VERSION 5.7 ;
  NOWIREEXTENSIONATPIN ON ;
  DIVIDERCHAR "/" ;
  BUSBITCHARS "[]" ;
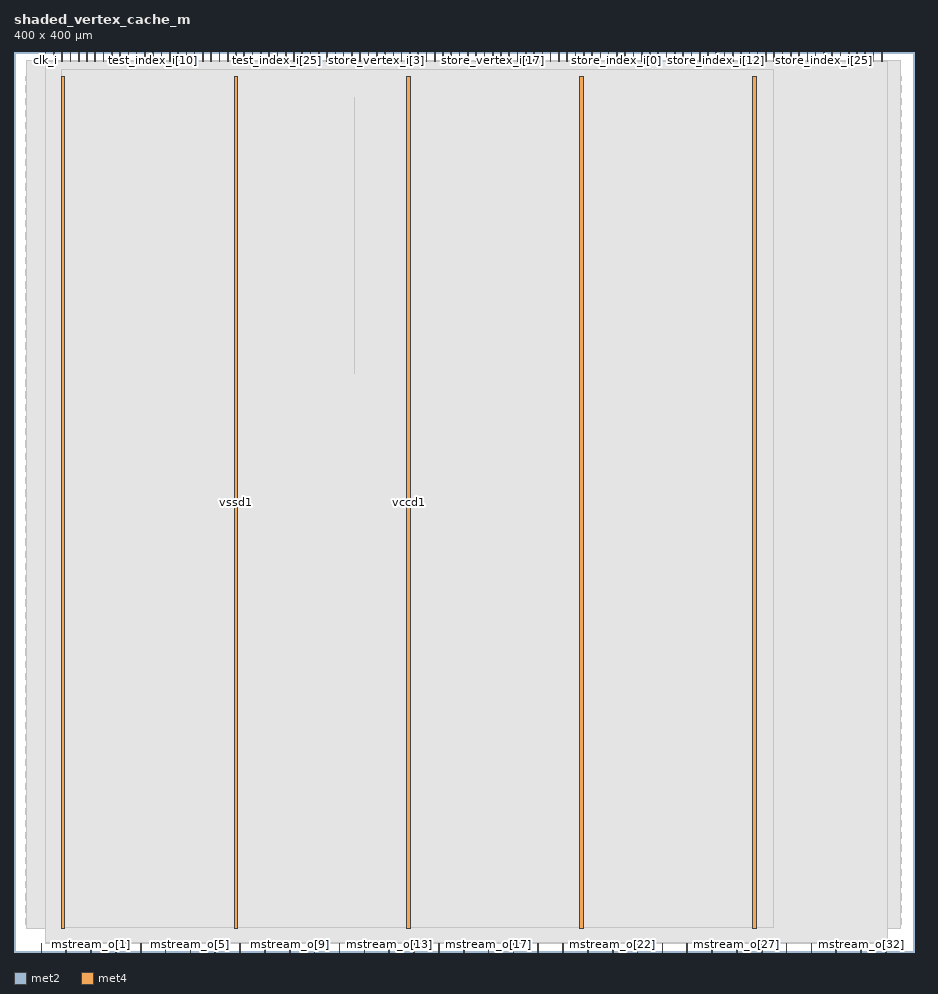
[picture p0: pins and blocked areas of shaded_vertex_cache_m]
MACRO shaded_vertex_cache_m
  CLASS BLOCK ;
  FOREIGN shaded_vertex_cache_m ;
  ORIGIN 0.000 0.000 ;
  SIZE 400.000 BY 400.000 ;
  PIN clear_i
    DIRECTION INPUT ;
    USE SIGNAL ;
    ANTENNAGATEAREA 0.196500 ;
    PORT
      LAYER met2 ;
        RECT 21.250 396.000 21.530 400.000 ;
    END
  END clear_i
  PIN clk_i
    DIRECTION INPUT ;
    USE SIGNAL ;
    ANTENNAGATEAREA 0.852000 ;
    PORT
      LAYER met2 ;
        RECT 13.890 396.000 14.170 400.000 ;
    END
  END clk_i
  PIN mstream_i
    DIRECTION INPUT ;
    USE SIGNAL ;
    PORT
      LAYER met2 ;
        RECT 12.050 0.000 12.330 4.000 ;
    END
  END mstream_i
  PIN mstream_o[0]
    DIRECTION OUTPUT TRISTATE ;
    USE SIGNAL ;
    ANTENNADIFFAREA 2.673000 ;
    PORT
      LAYER met2 ;
        RECT 23.090 0.000 23.370 4.000 ;
    END
  END mstream_o[0]
  PIN mstream_o[10]
    DIRECTION OUTPUT TRISTATE ;
    USE SIGNAL ;
    ANTENNADIFFAREA 2.673000 ;
    PORT
      LAYER met2 ;
        RECT 133.490 0.000 133.770 4.000 ;
    END
  END mstream_o[10]
  PIN mstream_o[11]
    DIRECTION OUTPUT TRISTATE ;
    USE SIGNAL ;
    ANTENNADIFFAREA 2.673000 ;
    PORT
      LAYER met2 ;
        RECT 144.530 0.000 144.810 4.000 ;
    END
  END mstream_o[11]
  PIN mstream_o[12]
    DIRECTION OUTPUT TRISTATE ;
    USE SIGNAL ;
    ANTENNADIFFAREA 2.673000 ;
    PORT
      LAYER met2 ;
        RECT 155.570 0.000 155.850 4.000 ;
    END
  END mstream_o[12]
  PIN mstream_o[13]
    DIRECTION OUTPUT TRISTATE ;
    USE SIGNAL ;
    ANTENNADIFFAREA 2.673000 ;
    PORT
      LAYER met2 ;
        RECT 166.610 0.000 166.890 4.000 ;
    END
  END mstream_o[13]
  PIN mstream_o[14]
    DIRECTION OUTPUT TRISTATE ;
    USE SIGNAL ;
    ANTENNADIFFAREA 2.673000 ;
    PORT
      LAYER met2 ;
        RECT 177.650 0.000 177.930 4.000 ;
    END
  END mstream_o[14]
  PIN mstream_o[15]
    DIRECTION OUTPUT TRISTATE ;
    USE SIGNAL ;
    ANTENNADIFFAREA 2.673000 ;
    PORT
      LAYER met2 ;
        RECT 188.690 0.000 188.970 4.000 ;
    END
  END mstream_o[15]
  PIN mstream_o[16]
    DIRECTION OUTPUT TRISTATE ;
    USE SIGNAL ;
    ANTENNADIFFAREA 2.673000 ;
    PORT
      LAYER met2 ;
        RECT 199.730 0.000 200.010 4.000 ;
    END
  END mstream_o[16]
  PIN mstream_o[17]
    DIRECTION OUTPUT TRISTATE ;
    USE SIGNAL ;
    ANTENNADIFFAREA 2.673000 ;
    PORT
      LAYER met2 ;
        RECT 210.770 0.000 211.050 4.000 ;
    END
  END mstream_o[17]
  PIN mstream_o[18]
    DIRECTION OUTPUT TRISTATE ;
    USE SIGNAL ;
    ANTENNADIFFAREA 2.673000 ;
    PORT
      LAYER met2 ;
        RECT 221.810 0.000 222.090 4.000 ;
    END
  END mstream_o[18]
  PIN mstream_o[19]
    DIRECTION OUTPUT TRISTATE ;
    USE SIGNAL ;
    ANTENNADIFFAREA 2.673000 ;
    PORT
      LAYER met2 ;
        RECT 232.850 0.000 233.130 4.000 ;
    END
  END mstream_o[19]
  PIN mstream_o[1]
    DIRECTION OUTPUT TRISTATE ;
    USE SIGNAL ;
    ANTENNADIFFAREA 2.673000 ;
    PORT
      LAYER met2 ;
        RECT 34.130 0.000 34.410 4.000 ;
    END
  END mstream_o[1]
  PIN mstream_o[20]
    DIRECTION OUTPUT TRISTATE ;
    USE SIGNAL ;
    ANTENNADIFFAREA 2.673000 ;
    PORT
      LAYER met2 ;
        RECT 243.890 0.000 244.170 4.000 ;
    END
  END mstream_o[20]
  PIN mstream_o[21]
    DIRECTION OUTPUT TRISTATE ;
    USE SIGNAL ;
    ANTENNADIFFAREA 2.673000 ;
    PORT
      LAYER met2 ;
        RECT 254.930 0.000 255.210 4.000 ;
    END
  END mstream_o[21]
  PIN mstream_o[22]
    DIRECTION OUTPUT TRISTATE ;
    USE SIGNAL ;
    ANTENNADIFFAREA 2.673000 ;
    PORT
      LAYER met2 ;
        RECT 265.970 0.000 266.250 4.000 ;
    END
  END mstream_o[22]
  PIN mstream_o[23]
    DIRECTION OUTPUT TRISTATE ;
    USE SIGNAL ;
    ANTENNADIFFAREA 2.673000 ;
    PORT
      LAYER met2 ;
        RECT 277.010 0.000 277.290 4.000 ;
    END
  END mstream_o[23]
  PIN mstream_o[24]
    DIRECTION OUTPUT TRISTATE ;
    USE SIGNAL ;
    ANTENNADIFFAREA 2.673000 ;
    PORT
      LAYER met2 ;
        RECT 288.050 0.000 288.330 4.000 ;
    END
  END mstream_o[24]
  PIN mstream_o[25]
    DIRECTION OUTPUT TRISTATE ;
    USE SIGNAL ;
    ANTENNADIFFAREA 2.673000 ;
    PORT
      LAYER met2 ;
        RECT 299.090 0.000 299.370 4.000 ;
    END
  END mstream_o[25]
  PIN mstream_o[26]
    DIRECTION OUTPUT TRISTATE ;
    USE SIGNAL ;
    ANTENNADIFFAREA 2.673000 ;
    PORT
      LAYER met2 ;
        RECT 310.130 0.000 310.410 4.000 ;
    END
  END mstream_o[26]
  PIN mstream_o[27]
    DIRECTION OUTPUT TRISTATE ;
    USE SIGNAL ;
    ANTENNADIFFAREA 2.673000 ;
    PORT
      LAYER met2 ;
        RECT 321.170 0.000 321.450 4.000 ;
    END
  END mstream_o[27]
  PIN mstream_o[28]
    DIRECTION OUTPUT TRISTATE ;
    USE SIGNAL ;
    ANTENNADIFFAREA 2.673000 ;
    PORT
      LAYER met2 ;
        RECT 332.210 0.000 332.490 4.000 ;
    END
  END mstream_o[28]
  PIN mstream_o[29]
    DIRECTION OUTPUT TRISTATE ;
    USE SIGNAL ;
    ANTENNADIFFAREA 2.673000 ;
    PORT
      LAYER met2 ;
        RECT 343.250 0.000 343.530 4.000 ;
    END
  END mstream_o[29]
  PIN mstream_o[2]
    DIRECTION OUTPUT TRISTATE ;
    USE SIGNAL ;
    ANTENNADIFFAREA 2.673000 ;
    PORT
      LAYER met2 ;
        RECT 45.170 0.000 45.450 4.000 ;
    END
  END mstream_o[2]
  PIN mstream_o[30]
    DIRECTION OUTPUT TRISTATE ;
    USE SIGNAL ;
    ANTENNADIFFAREA 2.673000 ;
    PORT
      LAYER met2 ;
        RECT 354.290 0.000 354.570 4.000 ;
    END
  END mstream_o[30]
  PIN mstream_o[31]
    DIRECTION OUTPUT TRISTATE ;
    USE SIGNAL ;
    ANTENNADIFFAREA 2.673000 ;
    PORT
      LAYER met2 ;
        RECT 365.330 0.000 365.610 4.000 ;
    END
  END mstream_o[31]
  PIN mstream_o[32]
    DIRECTION OUTPUT TRISTATE ;
    USE SIGNAL ;
    ANTENNADIFFAREA 2.673000 ;
    PORT
      LAYER met2 ;
        RECT 376.370 0.000 376.650 4.000 ;
    END
  END mstream_o[32]
  PIN mstream_o[33]
    DIRECTION OUTPUT TRISTATE ;
    USE SIGNAL ;
    PORT
      LAYER met2 ;
        RECT 387.410 0.000 387.690 4.000 ;
    END
  END mstream_o[33]
  PIN mstream_o[3]
    DIRECTION OUTPUT TRISTATE ;
    USE SIGNAL ;
    ANTENNADIFFAREA 2.673000 ;
    PORT
      LAYER met2 ;
        RECT 56.210 0.000 56.490 4.000 ;
    END
  END mstream_o[3]
  PIN mstream_o[4]
    DIRECTION OUTPUT TRISTATE ;
    USE SIGNAL ;
    ANTENNADIFFAREA 2.673000 ;
    PORT
      LAYER met2 ;
        RECT 67.250 0.000 67.530 4.000 ;
    END
  END mstream_o[4]
  PIN mstream_o[5]
    DIRECTION OUTPUT TRISTATE ;
    USE SIGNAL ;
    ANTENNADIFFAREA 2.673000 ;
    PORT
      LAYER met2 ;
        RECT 78.290 0.000 78.570 4.000 ;
    END
  END mstream_o[5]
  PIN mstream_o[6]
    DIRECTION OUTPUT TRISTATE ;
    USE SIGNAL ;
    ANTENNADIFFAREA 2.673000 ;
    PORT
      LAYER met2 ;
        RECT 89.330 0.000 89.610 4.000 ;
    END
  END mstream_o[6]
  PIN mstream_o[7]
    DIRECTION OUTPUT TRISTATE ;
    USE SIGNAL ;
    ANTENNADIFFAREA 2.673000 ;
    PORT
      LAYER met2 ;
        RECT 100.370 0.000 100.650 4.000 ;
    END
  END mstream_o[7]
  PIN mstream_o[8]
    DIRECTION OUTPUT TRISTATE ;
    USE SIGNAL ;
    ANTENNADIFFAREA 2.673000 ;
    PORT
      LAYER met2 ;
        RECT 111.410 0.000 111.690 4.000 ;
    END
  END mstream_o[8]
  PIN mstream_o[9]
    DIRECTION OUTPUT TRISTATE ;
    USE SIGNAL ;
    ANTENNADIFFAREA 2.673000 ;
    PORT
      LAYER met2 ;
        RECT 122.450 0.000 122.730 4.000 ;
    END
  END mstream_o[9]
  PIN nrst_i
    DIRECTION INPUT ;
    USE SIGNAL ;
    ANTENNAGATEAREA 0.213000 ;
    PORT
      LAYER met2 ;
        RECT 17.570 396.000 17.850 400.000 ;
    END
  END nrst_i
  PIN store_index_i[0]
    DIRECTION INPUT ;
    USE SIGNAL ;
    ANTENNAGATEAREA 0.196500 ;
    PORT
      LAYER met2 ;
        RECT 267.810 396.000 268.090 400.000 ;
    END
  END store_index_i[0]
  PIN store_index_i[10]
    DIRECTION INPUT ;
    USE SIGNAL ;
    ANTENNAGATEAREA 0.196500 ;
    PORT
      LAYER met2 ;
        RECT 304.610 396.000 304.890 400.000 ;
    END
  END store_index_i[10]
  PIN store_index_i[11]
    DIRECTION INPUT ;
    USE SIGNAL ;
    ANTENNAGATEAREA 0.196500 ;
    PORT
      LAYER met2 ;
        RECT 308.290 396.000 308.570 400.000 ;
    END
  END store_index_i[11]
  PIN store_index_i[12]
    DIRECTION INPUT ;
    USE SIGNAL ;
    ANTENNAGATEAREA 0.196500 ;
    PORT
      LAYER met2 ;
        RECT 311.970 396.000 312.250 400.000 ;
    END
  END store_index_i[12]
  PIN store_index_i[13]
    DIRECTION INPUT ;
    USE SIGNAL ;
    ANTENNAGATEAREA 0.196500 ;
    PORT
      LAYER met2 ;
        RECT 315.650 396.000 315.930 400.000 ;
    END
  END store_index_i[13]
  PIN store_index_i[14]
    DIRECTION INPUT ;
    USE SIGNAL ;
    ANTENNAGATEAREA 0.196500 ;
    PORT
      LAYER met2 ;
        RECT 319.330 396.000 319.610 400.000 ;
    END
  END store_index_i[14]
  PIN store_index_i[15]
    DIRECTION INPUT ;
    USE SIGNAL ;
    ANTENNAGATEAREA 0.196500 ;
    PORT
      LAYER met2 ;
        RECT 323.010 396.000 323.290 400.000 ;
    END
  END store_index_i[15]
  PIN store_index_i[16]
    DIRECTION INPUT ;
    USE SIGNAL ;
    ANTENNAGATEAREA 0.196500 ;
    PORT
      LAYER met2 ;
        RECT 326.690 396.000 326.970 400.000 ;
    END
  END store_index_i[16]
  PIN store_index_i[17]
    DIRECTION INPUT ;
    USE SIGNAL ;
    ANTENNAGATEAREA 0.126000 ;
    PORT
      LAYER met2 ;
        RECT 330.370 396.000 330.650 400.000 ;
    END
  END store_index_i[17]
  PIN store_index_i[18]
    DIRECTION INPUT ;
    USE SIGNAL ;
    ANTENNAGATEAREA 0.196500 ;
    PORT
      LAYER met2 ;
        RECT 334.050 396.000 334.330 400.000 ;
    END
  END store_index_i[18]
  PIN store_index_i[19]
    DIRECTION INPUT ;
    USE SIGNAL ;
    ANTENNAGATEAREA 0.196500 ;
    PORT
      LAYER met2 ;
        RECT 337.730 396.000 338.010 400.000 ;
    END
  END store_index_i[19]
  PIN store_index_i[1]
    DIRECTION INPUT ;
    USE SIGNAL ;
    ANTENNAGATEAREA 0.196500 ;
    PORT
      LAYER met2 ;
        RECT 271.490 396.000 271.770 400.000 ;
    END
  END store_index_i[1]
  PIN store_index_i[20]
    DIRECTION INPUT ;
    USE SIGNAL ;
    ANTENNAGATEAREA 0.196500 ;
    PORT
      LAYER met2 ;
        RECT 341.410 396.000 341.690 400.000 ;
    END
  END store_index_i[20]
  PIN store_index_i[21]
    DIRECTION INPUT ;
    USE SIGNAL ;
    ANTENNAGATEAREA 0.213000 ;
    PORT
      LAYER met2 ;
        RECT 345.090 396.000 345.370 400.000 ;
    END
  END store_index_i[21]
  PIN store_index_i[22]
    DIRECTION INPUT ;
    USE SIGNAL ;
    ANTENNAGATEAREA 0.213000 ;
    PORT
      LAYER met2 ;
        RECT 348.770 396.000 349.050 400.000 ;
    END
  END store_index_i[22]
  PIN store_index_i[23]
    DIRECTION INPUT ;
    USE SIGNAL ;
    ANTENNAGATEAREA 0.213000 ;
    PORT
      LAYER met2 ;
        RECT 352.450 396.000 352.730 400.000 ;
    END
  END store_index_i[23]
  PIN store_index_i[24]
    DIRECTION INPUT ;
    USE SIGNAL ;
    ANTENNAGATEAREA 0.213000 ;
    PORT
      LAYER met2 ;
        RECT 356.130 396.000 356.410 400.000 ;
    END
  END store_index_i[24]
  PIN store_index_i[25]
    DIRECTION INPUT ;
    USE SIGNAL ;
    ANTENNAGATEAREA 0.213000 ;
    PORT
      LAYER met2 ;
        RECT 359.810 396.000 360.090 400.000 ;
    END
  END store_index_i[25]
  PIN store_index_i[26]
    DIRECTION INPUT ;
    USE SIGNAL ;
    ANTENNAGATEAREA 0.213000 ;
    PORT
      LAYER met2 ;
        RECT 363.490 396.000 363.770 400.000 ;
    END
  END store_index_i[26]
  PIN store_index_i[27]
    DIRECTION INPUT ;
    USE SIGNAL ;
    ANTENNAGATEAREA 0.213000 ;
    PORT
      LAYER met2 ;
        RECT 367.170 396.000 367.450 400.000 ;
    END
  END store_index_i[27]
  PIN store_index_i[28]
    DIRECTION INPUT ;
    USE SIGNAL ;
    ANTENNAGATEAREA 0.213000 ;
    PORT
      LAYER met2 ;
        RECT 370.850 396.000 371.130 400.000 ;
    END
  END store_index_i[28]
  PIN store_index_i[29]
    DIRECTION INPUT ;
    USE SIGNAL ;
    ANTENNAGATEAREA 0.213000 ;
    PORT
      LAYER met2 ;
        RECT 374.530 396.000 374.810 400.000 ;
    END
  END store_index_i[29]
  PIN store_index_i[2]
    DIRECTION INPUT ;
    USE SIGNAL ;
    ANTENNAGATEAREA 0.196500 ;
    PORT
      LAYER met2 ;
        RECT 275.170 396.000 275.450 400.000 ;
    END
  END store_index_i[2]
  PIN store_index_i[30]
    DIRECTION INPUT ;
    USE SIGNAL ;
    ANTENNAGATEAREA 0.213000 ;
    PORT
      LAYER met2 ;
        RECT 378.210 396.000 378.490 400.000 ;
    END
  END store_index_i[30]
  PIN store_index_i[31]
    DIRECTION INPUT ;
    USE SIGNAL ;
    ANTENNAGATEAREA 0.196500 ;
    PORT
      LAYER met2 ;
        RECT 381.890 396.000 382.170 400.000 ;
    END
  END store_index_i[31]
  PIN store_index_i[3]
    DIRECTION INPUT ;
    USE SIGNAL ;
    ANTENNAGATEAREA 0.196500 ;
    PORT
      LAYER met2 ;
        RECT 278.850 396.000 279.130 400.000 ;
    END
  END store_index_i[3]
  PIN store_index_i[4]
    DIRECTION INPUT ;
    USE SIGNAL ;
    ANTENNAGATEAREA 0.196500 ;
    PORT
      LAYER met2 ;
        RECT 282.530 396.000 282.810 400.000 ;
    END
  END store_index_i[4]
  PIN store_index_i[5]
    DIRECTION INPUT ;
    USE SIGNAL ;
    ANTENNAGATEAREA 0.196500 ;
    PORT
      LAYER met2 ;
        RECT 286.210 396.000 286.490 400.000 ;
    END
  END store_index_i[5]
  PIN store_index_i[6]
    DIRECTION INPUT ;
    USE SIGNAL ;
    ANTENNAGATEAREA 0.196500 ;
    PORT
      LAYER met2 ;
        RECT 289.890 396.000 290.170 400.000 ;
    END
  END store_index_i[6]
  PIN store_index_i[7]
    DIRECTION INPUT ;
    USE SIGNAL ;
    ANTENNAGATEAREA 0.196500 ;
    PORT
      LAYER met2 ;
        RECT 293.570 396.000 293.850 400.000 ;
    END
  END store_index_i[7]
  PIN store_index_i[8]
    DIRECTION INPUT ;
    USE SIGNAL ;
    ANTENNAGATEAREA 0.196500 ;
    PORT
      LAYER met2 ;
        RECT 297.250 396.000 297.530 400.000 ;
    END
  END store_index_i[8]
  PIN store_index_i[9]
    DIRECTION INPUT ;
    USE SIGNAL ;
    ANTENNAGATEAREA 0.196500 ;
    PORT
      LAYER met2 ;
        RECT 300.930 396.000 301.210 400.000 ;
    END
  END store_index_i[9]
  PIN store_valid_i
    DIRECTION INPUT ;
    USE SIGNAL ;
    ANTENNAGATEAREA 0.213000 ;
    PORT
      LAYER met2 ;
        RECT 385.570 396.000 385.850 400.000 ;
    END
  END store_valid_i
  PIN store_vertex_i[0]
    DIRECTION INPUT ;
    USE SIGNAL ;
    ANTENNAGATEAREA 0.126000 ;
    PORT
      LAYER met2 ;
        RECT 150.050 396.000 150.330 400.000 ;
    END
  END store_vertex_i[0]
  PIN store_vertex_i[10]
    DIRECTION INPUT ;
    USE SIGNAL ;
    ANTENNAGATEAREA 0.196500 ;
    PORT
      LAYER met2 ;
        RECT 186.850 396.000 187.130 400.000 ;
    END
  END store_vertex_i[10]
  PIN store_vertex_i[11]
    DIRECTION INPUT ;
    USE SIGNAL ;
    ANTENNAGATEAREA 0.196500 ;
    PORT
      LAYER met2 ;
        RECT 190.530 396.000 190.810 400.000 ;
    END
  END store_vertex_i[11]
  PIN store_vertex_i[12]
    DIRECTION INPUT ;
    USE SIGNAL ;
    ANTENNAGATEAREA 0.196500 ;
    PORT
      LAYER met2 ;
        RECT 194.210 396.000 194.490 400.000 ;
    END
  END store_vertex_i[12]
  PIN store_vertex_i[13]
    DIRECTION INPUT ;
    USE SIGNAL ;
    ANTENNAGATEAREA 0.196500 ;
    PORT
      LAYER met2 ;
        RECT 197.890 396.000 198.170 400.000 ;
    END
  END store_vertex_i[13]
  PIN store_vertex_i[14]
    DIRECTION INPUT ;
    USE SIGNAL ;
    ANTENNAGATEAREA 0.196500 ;
    PORT
      LAYER met2 ;
        RECT 201.570 396.000 201.850 400.000 ;
    END
  END store_vertex_i[14]
  PIN store_vertex_i[15]
    DIRECTION INPUT ;
    USE SIGNAL ;
    ANTENNAGATEAREA 0.196500 ;
    PORT
      LAYER met2 ;
        RECT 205.250 396.000 205.530 400.000 ;
    END
  END store_vertex_i[15]
  PIN store_vertex_i[16]
    DIRECTION INPUT ;
    USE SIGNAL ;
    ANTENNAGATEAREA 0.196500 ;
    PORT
      LAYER met2 ;
        RECT 208.930 396.000 209.210 400.000 ;
    END
  END store_vertex_i[16]
  PIN store_vertex_i[17]
    DIRECTION INPUT ;
    USE SIGNAL ;
    ANTENNAGATEAREA 0.196500 ;
    PORT
      LAYER met2 ;
        RECT 212.610 396.000 212.890 400.000 ;
    END
  END store_vertex_i[17]
  PIN store_vertex_i[18]
    DIRECTION INPUT ;
    USE SIGNAL ;
    ANTENNAGATEAREA 0.196500 ;
    PORT
      LAYER met2 ;
        RECT 216.290 396.000 216.570 400.000 ;
    END
  END store_vertex_i[18]
  PIN store_vertex_i[19]
    DIRECTION INPUT ;
    USE SIGNAL ;
    ANTENNAGATEAREA 0.196500 ;
    PORT
      LAYER met2 ;
        RECT 219.970 396.000 220.250 400.000 ;
    END
  END store_vertex_i[19]
  PIN store_vertex_i[1]
    DIRECTION INPUT ;
    USE SIGNAL ;
    ANTENNAGATEAREA 0.196500 ;
    PORT
      LAYER met2 ;
        RECT 153.730 396.000 154.010 400.000 ;
    END
  END store_vertex_i[1]
  PIN store_vertex_i[20]
    DIRECTION INPUT ;
    USE SIGNAL ;
    ANTENNAGATEAREA 0.196500 ;
    PORT
      LAYER met2 ;
        RECT 223.650 396.000 223.930 400.000 ;
    END
  END store_vertex_i[20]
  PIN store_vertex_i[21]
    DIRECTION INPUT ;
    USE SIGNAL ;
    ANTENNAGATEAREA 0.196500 ;
    PORT
      LAYER met2 ;
        RECT 227.330 396.000 227.610 400.000 ;
    END
  END store_vertex_i[21]
  PIN store_vertex_i[22]
    DIRECTION INPUT ;
    USE SIGNAL ;
    ANTENNAGATEAREA 0.196500 ;
    PORT
      LAYER met2 ;
        RECT 231.010 396.000 231.290 400.000 ;
    END
  END store_vertex_i[22]
  PIN store_vertex_i[23]
    DIRECTION INPUT ;
    USE SIGNAL ;
    ANTENNAGATEAREA 0.196500 ;
    PORT
      LAYER met2 ;
        RECT 234.690 396.000 234.970 400.000 ;
    END
  END store_vertex_i[23]
  PIN store_vertex_i[24]
    DIRECTION INPUT ;
    USE SIGNAL ;
    ANTENNAGATEAREA 0.196500 ;
    PORT
      LAYER met2 ;
        RECT 238.370 396.000 238.650 400.000 ;
    END
  END store_vertex_i[24]
  PIN store_vertex_i[25]
    DIRECTION INPUT ;
    USE SIGNAL ;
    ANTENNAGATEAREA 0.196500 ;
    PORT
      LAYER met2 ;
        RECT 242.050 396.000 242.330 400.000 ;
    END
  END store_vertex_i[25]
  PIN store_vertex_i[26]
    DIRECTION INPUT ;
    USE SIGNAL ;
    ANTENNAGATEAREA 0.196500 ;
    PORT
      LAYER met2 ;
        RECT 245.730 396.000 246.010 400.000 ;
    END
  END store_vertex_i[26]
  PIN store_vertex_i[27]
    DIRECTION INPUT ;
    USE SIGNAL ;
    ANTENNAGATEAREA 0.196500 ;
    PORT
      LAYER met2 ;
        RECT 249.410 396.000 249.690 400.000 ;
    END
  END store_vertex_i[27]
  PIN store_vertex_i[28]
    DIRECTION INPUT ;
    USE SIGNAL ;
    ANTENNAGATEAREA 0.196500 ;
    PORT
      LAYER met2 ;
        RECT 253.090 396.000 253.370 400.000 ;
    END
  END store_vertex_i[28]
  PIN store_vertex_i[29]
    DIRECTION INPUT ;
    USE SIGNAL ;
    ANTENNAGATEAREA 0.196500 ;
    PORT
      LAYER met2 ;
        RECT 256.770 396.000 257.050 400.000 ;
    END
  END store_vertex_i[29]
  PIN store_vertex_i[2]
    DIRECTION INPUT ;
    USE SIGNAL ;
    ANTENNAGATEAREA 0.196500 ;
    PORT
      LAYER met2 ;
        RECT 157.410 396.000 157.690 400.000 ;
    END
  END store_vertex_i[2]
  PIN store_vertex_i[30]
    DIRECTION INPUT ;
    USE SIGNAL ;
    ANTENNAGATEAREA 0.196500 ;
    PORT
      LAYER met2 ;
        RECT 260.450 396.000 260.730 400.000 ;
    END
  END store_vertex_i[30]
  PIN store_vertex_i[31]
    DIRECTION INPUT ;
    USE SIGNAL ;
    ANTENNAGATEAREA 0.196500 ;
    PORT
      LAYER met2 ;
        RECT 264.130 396.000 264.410 400.000 ;
    END
  END store_vertex_i[31]
  PIN store_vertex_i[3]
    DIRECTION INPUT ;
    USE SIGNAL ;
    ANTENNAGATEAREA 0.196500 ;
    PORT
      LAYER met2 ;
        RECT 161.090 396.000 161.370 400.000 ;
    END
  END store_vertex_i[3]
  PIN store_vertex_i[4]
    DIRECTION INPUT ;
    USE SIGNAL ;
    ANTENNAGATEAREA 0.196500 ;
    PORT
      LAYER met2 ;
        RECT 164.770 396.000 165.050 400.000 ;
    END
  END store_vertex_i[4]
  PIN store_vertex_i[5]
    DIRECTION INPUT ;
    USE SIGNAL ;
    ANTENNAGATEAREA 0.196500 ;
    PORT
      LAYER met2 ;
        RECT 168.450 396.000 168.730 400.000 ;
    END
  END store_vertex_i[5]
  PIN store_vertex_i[6]
    DIRECTION INPUT ;
    USE SIGNAL ;
    ANTENNAGATEAREA 0.196500 ;
    PORT
      LAYER met2 ;
        RECT 172.130 396.000 172.410 400.000 ;
    END
  END store_vertex_i[6]
  PIN store_vertex_i[7]
    DIRECTION INPUT ;
    USE SIGNAL ;
    ANTENNAGATEAREA 0.196500 ;
    PORT
      LAYER met2 ;
        RECT 175.810 396.000 176.090 400.000 ;
    END
  END store_vertex_i[7]
  PIN store_vertex_i[8]
    DIRECTION INPUT ;
    USE SIGNAL ;
    ANTENNAGATEAREA 0.196500 ;
    PORT
      LAYER met2 ;
        RECT 179.490 396.000 179.770 400.000 ;
    END
  END store_vertex_i[8]
  PIN store_vertex_i[9]
    DIRECTION INPUT ;
    USE SIGNAL ;
    ANTENNAGATEAREA 0.196500 ;
    PORT
      LAYER met2 ;
        RECT 183.170 396.000 183.450 400.000 ;
    END
  END store_vertex_i[9]
  PIN test_found_o
    DIRECTION OUTPUT TRISTATE ;
    USE SIGNAL ;
    ANTENNADIFFAREA 2.673000 ;
    PORT
      LAYER met2 ;
        RECT 146.370 396.000 146.650 400.000 ;
    END
  END test_found_o
  PIN test_index_i[0]
    DIRECTION INPUT ;
    USE SIGNAL ;
    ANTENNAGATEAREA 0.213000 ;
    PORT
      LAYER met2 ;
        RECT 24.930 396.000 25.210 400.000 ;
    END
  END test_index_i[0]
  PIN test_index_i[10]
    DIRECTION INPUT ;
    USE SIGNAL ;
    ANTENNAGATEAREA 0.213000 ;
    PORT
      LAYER met2 ;
        RECT 61.730 396.000 62.010 400.000 ;
    END
  END test_index_i[10]
  PIN test_index_i[11]
    DIRECTION INPUT ;
    USE SIGNAL ;
    ANTENNAGATEAREA 0.213000 ;
    PORT
      LAYER met2 ;
        RECT 65.410 396.000 65.690 400.000 ;
    END
  END test_index_i[11]
  PIN test_index_i[12]
    DIRECTION INPUT ;
    USE SIGNAL ;
    ANTENNAGATEAREA 0.213000 ;
    PORT
      LAYER met2 ;
        RECT 69.090 396.000 69.370 400.000 ;
    END
  END test_index_i[12]
  PIN test_index_i[13]
    DIRECTION INPUT ;
    USE SIGNAL ;
    ANTENNAGATEAREA 0.213000 ;
    PORT
      LAYER met2 ;
        RECT 72.770 396.000 73.050 400.000 ;
    END
  END test_index_i[13]
  PIN test_index_i[14]
    DIRECTION INPUT ;
    USE SIGNAL ;
    ANTENNAGATEAREA 0.196500 ;
    PORT
      LAYER met2 ;
        RECT 76.450 396.000 76.730 400.000 ;
    END
  END test_index_i[14]
  PIN test_index_i[15]
    DIRECTION INPUT ;
    USE SIGNAL ;
    ANTENNAGATEAREA 0.126000 ;
    PORT
      LAYER met2 ;
        RECT 80.130 396.000 80.410 400.000 ;
    END
  END test_index_i[15]
  PIN test_index_i[16]
    DIRECTION INPUT ;
    USE SIGNAL ;
    ANTENNAGATEAREA 0.126000 ;
    PORT
      LAYER met2 ;
        RECT 83.810 396.000 84.090 400.000 ;
    END
  END test_index_i[16]
  PIN test_index_i[17]
    DIRECTION INPUT ;
    USE SIGNAL ;
    ANTENNAGATEAREA 0.196500 ;
    PORT
      LAYER met2 ;
        RECT 87.490 396.000 87.770 400.000 ;
    END
  END test_index_i[17]
  PIN test_index_i[18]
    DIRECTION INPUT ;
    USE SIGNAL ;
    ANTENNAGATEAREA 0.126000 ;
    PORT
      LAYER met2 ;
        RECT 91.170 396.000 91.450 400.000 ;
    END
  END test_index_i[18]
  PIN test_index_i[19]
    DIRECTION INPUT ;
    USE SIGNAL ;
    ANTENNAGATEAREA 0.196500 ;
    PORT
      LAYER met2 ;
        RECT 94.850 396.000 95.130 400.000 ;
    END
  END test_index_i[19]
  PIN test_index_i[1]
    DIRECTION INPUT ;
    USE SIGNAL ;
    ANTENNAGATEAREA 0.213000 ;
    PORT
      LAYER met2 ;
        RECT 28.610 396.000 28.890 400.000 ;
    END
  END test_index_i[1]
  PIN test_index_i[20]
    DIRECTION INPUT ;
    USE SIGNAL ;
    ANTENNAGATEAREA 0.126000 ;
    PORT
      LAYER met2 ;
        RECT 98.530 396.000 98.810 400.000 ;
    END
  END test_index_i[20]
  PIN test_index_i[21]
    DIRECTION INPUT ;
    USE SIGNAL ;
    ANTENNAGATEAREA 0.196500 ;
    PORT
      LAYER met2 ;
        RECT 102.210 396.000 102.490 400.000 ;
    END
  END test_index_i[21]
  PIN test_index_i[22]
    DIRECTION INPUT ;
    USE SIGNAL ;
    ANTENNAGATEAREA 0.196500 ;
    PORT
      LAYER met2 ;
        RECT 105.890 396.000 106.170 400.000 ;
    END
  END test_index_i[22]
  PIN test_index_i[23]
    DIRECTION INPUT ;
    USE SIGNAL ;
    ANTENNAGATEAREA 0.196500 ;
    PORT
      LAYER met2 ;
        RECT 109.570 396.000 109.850 400.000 ;
    END
  END test_index_i[23]
  PIN test_index_i[24]
    DIRECTION INPUT ;
    USE SIGNAL ;
    ANTENNAGATEAREA 0.196500 ;
    PORT
      LAYER met2 ;
        RECT 113.250 396.000 113.530 400.000 ;
    END
  END test_index_i[24]
  PIN test_index_i[25]
    DIRECTION INPUT ;
    USE SIGNAL ;
    ANTENNAGATEAREA 0.196500 ;
    PORT
      LAYER met2 ;
        RECT 116.930 396.000 117.210 400.000 ;
    END
  END test_index_i[25]
  PIN test_index_i[26]
    DIRECTION INPUT ;
    USE SIGNAL ;
    ANTENNAGATEAREA 0.196500 ;
    PORT
      LAYER met2 ;
        RECT 120.610 396.000 120.890 400.000 ;
    END
  END test_index_i[26]
  PIN test_index_i[27]
    DIRECTION INPUT ;
    USE SIGNAL ;
    ANTENNAGATEAREA 0.196500 ;
    PORT
      LAYER met2 ;
        RECT 124.290 396.000 124.570 400.000 ;
    END
  END test_index_i[27]
  PIN test_index_i[28]
    DIRECTION INPUT ;
    USE SIGNAL ;
    ANTENNAGATEAREA 0.196500 ;
    PORT
      LAYER met2 ;
        RECT 127.970 396.000 128.250 400.000 ;
    END
  END test_index_i[28]
  PIN test_index_i[29]
    DIRECTION INPUT ;
    USE SIGNAL ;
    ANTENNAGATEAREA 0.196500 ;
    PORT
      LAYER met2 ;
        RECT 131.650 396.000 131.930 400.000 ;
    END
  END test_index_i[29]
  PIN test_index_i[2]
    DIRECTION INPUT ;
    USE SIGNAL ;
    ANTENNAGATEAREA 0.213000 ;
    PORT
      LAYER met2 ;
        RECT 32.290 396.000 32.570 400.000 ;
    END
  END test_index_i[2]
  PIN test_index_i[30]
    DIRECTION INPUT ;
    USE SIGNAL ;
    ANTENNAGATEAREA 0.196500 ;
    PORT
      LAYER met2 ;
        RECT 135.330 396.000 135.610 400.000 ;
    END
  END test_index_i[30]
  PIN test_index_i[31]
    DIRECTION INPUT ;
    USE SIGNAL ;
    ANTENNAGATEAREA 0.196500 ;
    PORT
      LAYER met2 ;
        RECT 139.010 396.000 139.290 400.000 ;
    END
  END test_index_i[31]
  PIN test_index_i[3]
    DIRECTION INPUT ;
    USE SIGNAL ;
    ANTENNAGATEAREA 0.213000 ;
    PORT
      LAYER met2 ;
        RECT 35.970 396.000 36.250 400.000 ;
    END
  END test_index_i[3]
  PIN test_index_i[4]
    DIRECTION INPUT ;
    USE SIGNAL ;
    ANTENNAGATEAREA 0.159000 ;
    PORT
      LAYER met2 ;
        RECT 39.650 396.000 39.930 400.000 ;
    END
  END test_index_i[4]
  PIN test_index_i[5]
    DIRECTION INPUT ;
    USE SIGNAL ;
    ANTENNAGATEAREA 0.213000 ;
    PORT
      LAYER met2 ;
        RECT 43.330 396.000 43.610 400.000 ;
    END
  END test_index_i[5]
  PIN test_index_i[6]
    DIRECTION INPUT ;
    USE SIGNAL ;
    ANTENNAGATEAREA 0.213000 ;
    PORT
      LAYER met2 ;
        RECT 47.010 396.000 47.290 400.000 ;
    END
  END test_index_i[6]
  PIN test_index_i[7]
    DIRECTION INPUT ;
    USE SIGNAL ;
    ANTENNAGATEAREA 0.213000 ;
    PORT
      LAYER met2 ;
        RECT 50.690 396.000 50.970 400.000 ;
    END
  END test_index_i[7]
  PIN test_index_i[8]
    DIRECTION INPUT ;
    USE SIGNAL ;
    ANTENNAGATEAREA 0.126000 ;
    PORT
      LAYER met2 ;
        RECT 54.370 396.000 54.650 400.000 ;
    END
  END test_index_i[8]
  PIN test_index_i[9]
    DIRECTION INPUT ;
    USE SIGNAL ;
    ANTENNAGATEAREA 0.213000 ;
    PORT
      LAYER met2 ;
        RECT 58.050 396.000 58.330 400.000 ;
    END
  END test_index_i[9]
  PIN test_valid_i
    DIRECTION INPUT ;
    USE SIGNAL ;
    ANTENNAGATEAREA 0.196500 ;
    PORT
      LAYER met2 ;
        RECT 142.690 396.000 142.970 400.000 ;
    END
  END test_valid_i
  PIN vccd1
    DIRECTION INOUT ;
    USE POWER ;
    PORT
      LAYER met4 ;
        RECT 21.040 10.640 22.640 389.200 ;
    END
    PORT
      LAYER met4 ;
        RECT 174.640 10.640 176.240 389.200 ;
    END
    PORT
      LAYER met4 ;
        RECT 328.240 10.640 329.840 389.200 ;
    END
  END vccd1
  PIN vssd1
    DIRECTION INOUT ;
    USE GROUND ;
    PORT
      LAYER met4 ;
        RECT 97.840 10.640 99.440 389.200 ;
    END
    PORT
      LAYER met4 ;
        RECT 251.440 10.640 253.040 389.200 ;
    END
  END vssd1
  OBS
      LAYER nwell ;
        RECT 5.330 387.545 394.410 389.150 ;
        RECT 5.330 382.105 394.410 384.935 ;
        RECT 5.330 376.665 394.410 379.495 ;
        RECT 5.330 371.225 394.410 374.055 ;
        RECT 5.330 365.785 394.410 368.615 ;
        RECT 5.330 360.345 394.410 363.175 ;
        RECT 5.330 354.905 394.410 357.735 ;
        RECT 5.330 349.465 394.410 352.295 ;
        RECT 5.330 344.025 394.410 346.855 ;
        RECT 5.330 338.585 394.410 341.415 ;
        RECT 5.330 333.145 394.410 335.975 ;
        RECT 5.330 327.705 394.410 330.535 ;
        RECT 5.330 322.265 394.410 325.095 ;
        RECT 5.330 316.825 394.410 319.655 ;
        RECT 5.330 311.385 394.410 314.215 ;
        RECT 5.330 305.945 394.410 308.775 ;
        RECT 5.330 300.505 394.410 303.335 ;
        RECT 5.330 295.065 394.410 297.895 ;
        RECT 5.330 289.625 394.410 292.455 ;
        RECT 5.330 284.185 394.410 287.015 ;
        RECT 5.330 278.745 394.410 281.575 ;
        RECT 5.330 273.305 394.410 276.135 ;
        RECT 5.330 267.865 394.410 270.695 ;
        RECT 5.330 262.425 394.410 265.255 ;
        RECT 5.330 256.985 394.410 259.815 ;
        RECT 5.330 251.545 394.410 254.375 ;
        RECT 5.330 246.105 394.410 248.935 ;
        RECT 5.330 240.665 394.410 243.495 ;
        RECT 5.330 235.225 394.410 238.055 ;
        RECT 5.330 229.785 394.410 232.615 ;
        RECT 5.330 224.345 394.410 227.175 ;
        RECT 5.330 218.905 394.410 221.735 ;
        RECT 5.330 213.465 394.410 216.295 ;
        RECT 5.330 208.025 394.410 210.855 ;
        RECT 5.330 202.585 394.410 205.415 ;
        RECT 5.330 197.145 394.410 199.975 ;
        RECT 5.330 191.705 394.410 194.535 ;
        RECT 5.330 186.265 394.410 189.095 ;
        RECT 5.330 180.825 394.410 183.655 ;
        RECT 5.330 175.385 394.410 178.215 ;
        RECT 5.330 169.945 394.410 172.775 ;
        RECT 5.330 164.505 394.410 167.335 ;
        RECT 5.330 159.065 394.410 161.895 ;
        RECT 5.330 153.625 394.410 156.455 ;
        RECT 5.330 148.185 394.410 151.015 ;
        RECT 5.330 142.745 394.410 145.575 ;
        RECT 5.330 137.305 394.410 140.135 ;
        RECT 5.330 131.865 394.410 134.695 ;
        RECT 5.330 126.425 394.410 129.255 ;
        RECT 5.330 120.985 394.410 123.815 ;
        RECT 5.330 115.545 394.410 118.375 ;
        RECT 5.330 110.105 394.410 112.935 ;
        RECT 5.330 104.665 394.410 107.495 ;
        RECT 5.330 99.225 394.410 102.055 ;
        RECT 5.330 93.785 394.410 96.615 ;
        RECT 5.330 88.345 394.410 91.175 ;
        RECT 5.330 82.905 394.410 85.735 ;
        RECT 5.330 77.465 394.410 80.295 ;
        RECT 5.330 72.025 394.410 74.855 ;
        RECT 5.330 66.585 394.410 69.415 ;
        RECT 5.330 61.145 394.410 63.975 ;
        RECT 5.330 55.705 394.410 58.535 ;
        RECT 5.330 50.265 394.410 53.095 ;
        RECT 5.330 44.825 394.410 47.655 ;
        RECT 5.330 39.385 394.410 42.215 ;
        RECT 5.330 33.945 394.410 36.775 ;
        RECT 5.330 28.505 394.410 31.335 ;
        RECT 5.330 23.065 394.410 25.895 ;
        RECT 5.330 17.625 394.410 20.455 ;
        RECT 5.330 12.185 394.410 15.015 ;
      LAYER li1 ;
        RECT 5.520 10.795 394.220 389.045 ;
      LAYER met1 ;
        RECT 5.520 10.240 394.220 396.060 ;
      LAYER met2 ;
        RECT 14.450 395.720 17.290 396.170 ;
        RECT 18.130 395.720 20.970 396.170 ;
        RECT 21.810 395.720 24.650 396.170 ;
        RECT 25.490 395.720 28.330 396.170 ;
        RECT 29.170 395.720 32.010 396.170 ;
        RECT 32.850 395.720 35.690 396.170 ;
        RECT 36.530 395.720 39.370 396.170 ;
        RECT 40.210 395.720 43.050 396.170 ;
        RECT 43.890 395.720 46.730 396.170 ;
        RECT 47.570 395.720 50.410 396.170 ;
        RECT 51.250 395.720 54.090 396.170 ;
        RECT 54.930 395.720 57.770 396.170 ;
        RECT 58.610 395.720 61.450 396.170 ;
        RECT 62.290 395.720 65.130 396.170 ;
        RECT 65.970 395.720 68.810 396.170 ;
        RECT 69.650 395.720 72.490 396.170 ;
        RECT 73.330 395.720 76.170 396.170 ;
        RECT 77.010 395.720 79.850 396.170 ;
        RECT 80.690 395.720 83.530 396.170 ;
        RECT 84.370 395.720 87.210 396.170 ;
        RECT 88.050 395.720 90.890 396.170 ;
        RECT 91.730 395.720 94.570 396.170 ;
        RECT 95.410 395.720 98.250 396.170 ;
        RECT 99.090 395.720 101.930 396.170 ;
        RECT 102.770 395.720 105.610 396.170 ;
        RECT 106.450 395.720 109.290 396.170 ;
        RECT 110.130 395.720 112.970 396.170 ;
        RECT 113.810 395.720 116.650 396.170 ;
        RECT 117.490 395.720 120.330 396.170 ;
        RECT 121.170 395.720 124.010 396.170 ;
        RECT 124.850 395.720 127.690 396.170 ;
        RECT 128.530 395.720 131.370 396.170 ;
        RECT 132.210 395.720 135.050 396.170 ;
        RECT 135.890 395.720 138.730 396.170 ;
        RECT 139.570 395.720 142.410 396.170 ;
        RECT 143.250 395.720 146.090 396.170 ;
        RECT 146.930 395.720 149.770 396.170 ;
        RECT 150.610 395.720 153.450 396.170 ;
        RECT 154.290 395.720 157.130 396.170 ;
        RECT 157.970 395.720 160.810 396.170 ;
        RECT 161.650 395.720 164.490 396.170 ;
        RECT 165.330 395.720 168.170 396.170 ;
        RECT 169.010 395.720 171.850 396.170 ;
        RECT 172.690 395.720 175.530 396.170 ;
        RECT 176.370 395.720 179.210 396.170 ;
        RECT 180.050 395.720 182.890 396.170 ;
        RECT 183.730 395.720 186.570 396.170 ;
        RECT 187.410 395.720 190.250 396.170 ;
        RECT 191.090 395.720 193.930 396.170 ;
        RECT 194.770 395.720 197.610 396.170 ;
        RECT 198.450 395.720 201.290 396.170 ;
        RECT 202.130 395.720 204.970 396.170 ;
        RECT 205.810 395.720 208.650 396.170 ;
        RECT 209.490 395.720 212.330 396.170 ;
        RECT 213.170 395.720 216.010 396.170 ;
        RECT 216.850 395.720 219.690 396.170 ;
        RECT 220.530 395.720 223.370 396.170 ;
        RECT 224.210 395.720 227.050 396.170 ;
        RECT 227.890 395.720 230.730 396.170 ;
        RECT 231.570 395.720 234.410 396.170 ;
        RECT 235.250 395.720 238.090 396.170 ;
        RECT 238.930 395.720 241.770 396.170 ;
        RECT 242.610 395.720 245.450 396.170 ;
        RECT 246.290 395.720 249.130 396.170 ;
        RECT 249.970 395.720 252.810 396.170 ;
        RECT 253.650 395.720 256.490 396.170 ;
        RECT 257.330 395.720 260.170 396.170 ;
        RECT 261.010 395.720 263.850 396.170 ;
        RECT 264.690 395.720 267.530 396.170 ;
        RECT 268.370 395.720 271.210 396.170 ;
        RECT 272.050 395.720 274.890 396.170 ;
        RECT 275.730 395.720 278.570 396.170 ;
        RECT 279.410 395.720 282.250 396.170 ;
        RECT 283.090 395.720 285.930 396.170 ;
        RECT 286.770 395.720 289.610 396.170 ;
        RECT 290.450 395.720 293.290 396.170 ;
        RECT 294.130 395.720 296.970 396.170 ;
        RECT 297.810 395.720 300.650 396.170 ;
        RECT 301.490 395.720 304.330 396.170 ;
        RECT 305.170 395.720 308.010 396.170 ;
        RECT 308.850 395.720 311.690 396.170 ;
        RECT 312.530 395.720 315.370 396.170 ;
        RECT 316.210 395.720 319.050 396.170 ;
        RECT 319.890 395.720 322.730 396.170 ;
        RECT 323.570 395.720 326.410 396.170 ;
        RECT 327.250 395.720 330.090 396.170 ;
        RECT 330.930 395.720 333.770 396.170 ;
        RECT 334.610 395.720 337.450 396.170 ;
        RECT 338.290 395.720 341.130 396.170 ;
        RECT 341.970 395.720 344.810 396.170 ;
        RECT 345.650 395.720 348.490 396.170 ;
        RECT 349.330 395.720 352.170 396.170 ;
        RECT 353.010 395.720 355.850 396.170 ;
        RECT 356.690 395.720 359.530 396.170 ;
        RECT 360.370 395.720 363.210 396.170 ;
        RECT 364.050 395.720 366.890 396.170 ;
        RECT 367.730 395.720 370.570 396.170 ;
        RECT 371.410 395.720 374.250 396.170 ;
        RECT 375.090 395.720 377.930 396.170 ;
        RECT 378.770 395.720 381.610 396.170 ;
        RECT 382.450 395.720 385.290 396.170 ;
        RECT 386.130 395.720 388.140 396.170 ;
        RECT 13.900 4.280 388.140 395.720 ;
        RECT 13.900 3.670 22.810 4.280 ;
        RECT 23.650 3.670 33.850 4.280 ;
        RECT 34.690 3.670 44.890 4.280 ;
        RECT 45.730 3.670 55.930 4.280 ;
        RECT 56.770 3.670 66.970 4.280 ;
        RECT 67.810 3.670 78.010 4.280 ;
        RECT 78.850 3.670 89.050 4.280 ;
        RECT 89.890 3.670 100.090 4.280 ;
        RECT 100.930 3.670 111.130 4.280 ;
        RECT 111.970 3.670 122.170 4.280 ;
        RECT 123.010 3.670 133.210 4.280 ;
        RECT 134.050 3.670 144.250 4.280 ;
        RECT 145.090 3.670 155.290 4.280 ;
        RECT 156.130 3.670 166.330 4.280 ;
        RECT 167.170 3.670 177.370 4.280 ;
        RECT 178.210 3.670 188.410 4.280 ;
        RECT 189.250 3.670 199.450 4.280 ;
        RECT 200.290 3.670 210.490 4.280 ;
        RECT 211.330 3.670 221.530 4.280 ;
        RECT 222.370 3.670 232.570 4.280 ;
        RECT 233.410 3.670 243.610 4.280 ;
        RECT 244.450 3.670 254.650 4.280 ;
        RECT 255.490 3.670 265.690 4.280 ;
        RECT 266.530 3.670 276.730 4.280 ;
        RECT 277.570 3.670 287.770 4.280 ;
        RECT 288.610 3.670 298.810 4.280 ;
        RECT 299.650 3.670 309.850 4.280 ;
        RECT 310.690 3.670 320.890 4.280 ;
        RECT 321.730 3.670 331.930 4.280 ;
        RECT 332.770 3.670 342.970 4.280 ;
        RECT 343.810 3.670 354.010 4.280 ;
        RECT 354.850 3.670 365.050 4.280 ;
        RECT 365.890 3.670 376.090 4.280 ;
        RECT 376.930 3.670 387.130 4.280 ;
        RECT 387.970 3.670 388.140 4.280 ;
      LAYER met3 ;
        RECT 21.050 10.715 337.575 392.185 ;
      LAYER met4 ;
        RECT 151.175 257.215 151.505 379.945 ;
  END
END shaded_vertex_cache_m
END LIBRARY

